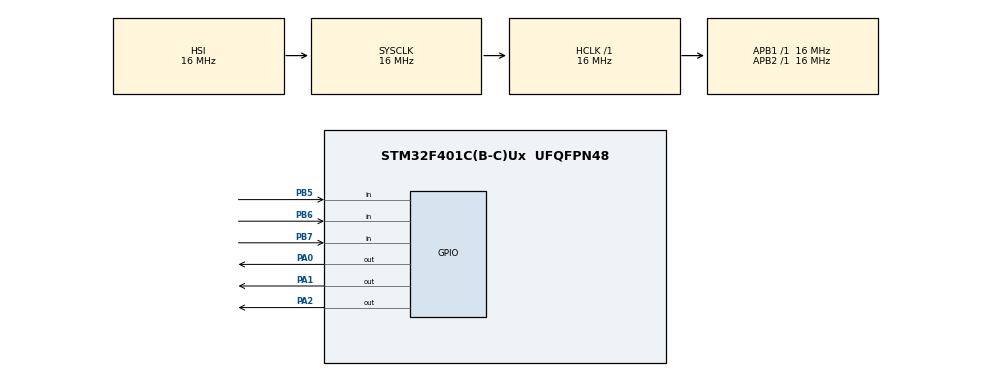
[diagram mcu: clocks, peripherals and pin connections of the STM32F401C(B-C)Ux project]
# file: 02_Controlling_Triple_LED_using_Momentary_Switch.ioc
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Mcu.Family=STM32F4
Mcu.Name=STM32F401C(B-C)Ux
Mcu.Package=UFQFPN48
NVIC.PriorityGroup=NVIC_PRIORITYGROUP_4
PA0-WKUP.Signal=GPIO_Output
PA1.Signal=GPIO_Output
PA2.Signal=GPIO_Output
PB5.Signal=GPIO_Input
PB6.Signal=GPIO_Input
PB7.Signal=GPIO_Input
ProjectManager.HeapSize=0x200
ProjectManager.StackSize=0x400
ProjectManager.TargetToolchain=STM32CubeIDE
RCC.AHBFreq_Value=16000000
RCC.APB1Freq_Value=16000000
RCC.APB2Freq_Value=16000000
RCC.CortexFreq_Value=16000000
RCC.HSE_VALUE=25000000
RCC.HSI_VALUE=16000000
RCC.LSE_VALUE=32768
RCC.SYSCLKFreq_VALUE=16000000
RCC.VCOOutputFreq_Value=192000000
board=custom

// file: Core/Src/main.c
/* USER CODE BEGIN Header */
/**
  ******************************************************************************
  * @file           : main.c
  * @brief          : Main program body
  ******************************************************************************
  * @attention
  *
  * Copyright (c) 2025 STMicroelectronics.
  * All rights reserved.
  *
  * This software is licensed under terms that can be found in the LICENSE file
  * in the root directory of this software component.
  * If no LICENSE file comes with this software, it is provided AS-IS.
  *
  ******************************************************************************
  */
/* USER CODE END Header */
#include "main.h"

void SystemClock_Config(void);
static void MX_GPIO_Init(void);

int main(void)
{

  /* MCU Configuration--------------------------------------------------------*/

  /* Reset of all peripherals, Initializes the Flash interface and the Systick. */
  HAL_Init();

  /* Configure the system clock */
  SystemClock_Config();

  /* Initialize all configured peripherals */
  MX_GPIO_Init();

  /* Infinite loop */
  /* USER CODE BEGIN WHILE */
  while (1)
  {
	  GPIO_PinState btn1 = HAL_GPIO_ReadPin(GPIOB, GPIO_PIN_3);
	  GPIO_PinState btn2 = HAL_GPIO_ReadPin(GPIOB, GPIO_PIN_4);
	  GPIO_PinState btn3 = HAL_GPIO_ReadPin(GPIOB, GPIO_PIN_5);

	  // Control LEDs based on button state
	  HAL_GPIO_WritePin(GPIOA, GPIO_PIN_0, (btn1 == GPIO_PIN_RESET) ? GPIO_PIN_SET : GPIO_PIN_RESET);
	  HAL_GPIO_WritePin(GPIOA, GPIO_PIN_1, (btn2 == GPIO_PIN_RESET) ? GPIO_PIN_SET : GPIO_PIN_RESET);
	  HAL_GPIO_WritePin(GPIOA, GPIO_PIN_2, (btn3 == GPIO_PIN_RESET) ? GPIO_PIN_SET : GPIO_PIN_RESET);
  }
  /* USER CODE END 3 */
}

void SystemClock_Config(void)
{
  RCC_OscInitTypeDef RCC_OscInitStruct = {0};
  RCC_ClkInitTypeDef RCC_ClkInitStruct = {0};

  /** Configure the main internal regulator output voltage
  */
  __HAL_RCC_PWR_CLK_ENABLE();
  __HAL_PWR_VOLTAGESCALING_CONFIG(PWR_REGULATOR_VOLTAGE_SCALE2);

  /** Initializes the RCC Oscillators according to the specified parameters
  * in the RCC_OscInitTypeDef structure.
  */
  RCC_OscInitStruct.OscillatorType = RCC_OSCILLATORTYPE_HSI;
  RCC_OscInitStruct.HSIState = RCC_HSI_ON;
  RCC_OscInitStruct.HSICalibrationValue = RCC_HSICALIBRATION_DEFAULT;
  RCC_OscInitStruct.PLL.PLLState = RCC_PLL_NONE;
  if (HAL_RCC_OscConfig(&RCC_OscInitStruct) != HAL_OK)
  {
    Error_Handler();
  }

  /** Initializes the CPU, AHB and APB buses clocks
  */
  RCC_ClkInitStruct.ClockType = RCC_CLOCKTYPE_HCLK|RCC_CLOCKTYPE_SYSCLK
                              |RCC_CLOCKTYPE_PCLK1|RCC_CLOCKTYPE_PCLK2;
  RCC_ClkInitStruct.SYSCLKSource = RCC_SYSCLKSOURCE_HSI;
  RCC_ClkInitStruct.AHBCLKDivider = RCC_SYSCLK_DIV1;
  RCC_ClkInitStruct.APB1CLKDivider = RCC_HCLK_DIV1;
  RCC_ClkInitStruct.APB2CLKDivider = RCC_HCLK_DIV1;

  if (HAL_RCC_ClockConfig(&RCC_ClkInitStruct, FLASH_LATENCY_0) != HAL_OK)
  {
    Error_Handler();
  }
}

static void MX_GPIO_Init(void)
{
  GPIO_InitTypeDef GPIO_InitStruct = {0};

  /* GPIO Ports Clock Enable */
  __HAL_RCC_GPIOA_CLK_ENABLE();
  __HAL_RCC_GPIOB_CLK_ENABLE();

  /*Configure GPIO pin Output Level */
  HAL_GPIO_WritePin(GPIOA, GPIO_PIN_0|GPIO_PIN_1|GPIO_PIN_2, GPIO_PIN_RESET);

  // LED Pins: PA0, PA1, PA2
  GPIO_InitStruct.Pin = GPIO_PIN_0 | GPIO_PIN_1 | GPIO_PIN_2;
  GPIO_InitStruct.Mode = GPIO_MODE_OUTPUT_PP;
  GPIO_InitStruct.Pull = GPIO_NOPULL;
  GPIO_InitStruct.Speed = GPIO_SPEED_FREQ_LOW;
  HAL_GPIO_Init(GPIOA, &GPIO_InitStruct);

  // Button Pins: PB3, PB4, PB5
  GPIO_InitStruct.Pin = GPIO_PIN_3 | GPIO_PIN_4 | GPIO_PIN_5;
  GPIO_InitStruct.Mode = GPIO_MODE_INPUT;
  GPIO_InitStruct.Pull = GPIO_PULLUP;
  HAL_GPIO_Init(GPIOB, &GPIO_InitStruct);

}

void Error_Handler(void)
{
  __disable_irq();
  while (1)
  {
  }
}
